VERSION 5.8 ;
UNITS
  DATABASE MICRONS 1000 ;
END UNITS
SITE core
  CLASS CORE ;
  SIZE 0.5 BY 2.0 ;
END core
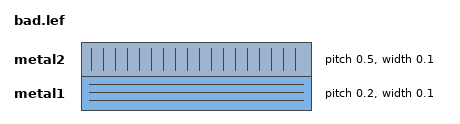
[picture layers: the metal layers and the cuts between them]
LAYER metal1
  TYPE ROUTING ;
  DIRECTION HORIZONTAL ;
  PITCH 0.2 ;
  WIDTH 0.1 ;
END metal1
LAYER metal2
  TYPE ROUTING ;
  DIRECTION VERTICAL ;
  PITCH 0.5 ;
  OFFSET 0.25 ;
  WIDTH 0.1 ;
END metal2
# clean: 0.5 x 2.0 = area 1, pins on track crossings
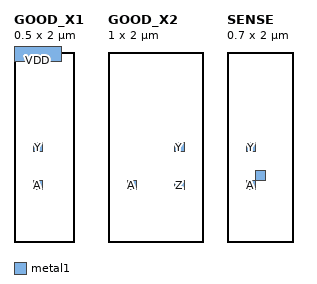
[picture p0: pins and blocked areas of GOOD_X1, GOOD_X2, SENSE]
MACRO GOOD_X1
  CLASS CORE ;
  SIZE 0.5 BY 2.0 ;
  SITE core ;
  PIN A
    DIRECTION INPUT ;
    PORT
      LAYER metal1 ;
        RECT 0.20 0.55 0.30 0.65 ;
    END
  END A
  PIN Y
    DIRECTION OUTPUT ;
    PORT
      LAYER metal1 ;
        RECT 0.20 0.95 0.30 1.05 ;
    END
  END Y
  PIN VDD
    DIRECTION INOUT ;
    USE POWER ;
    PORT
      LAYER metal1 ;
        RECT 0 1.9 0.5 2.1 ;
    END
  END VDD
END GOOD_X1
# LEF002: 1 x 2 = 2, the Liberty area is 0.9. LEF003: A is an output here, and there is a pin Z
MACRO GOOD_X2
  CLASS CORE ;
  SIZE 1.0 BY 2.0 ;
  SITE core ;
  PIN A
    DIRECTION OUTPUT ;
    PORT
      LAYER metal1 ;
        RECT 0.20 0.55 0.30 0.65 ;
    END
  END A
  PIN Y
    DIRECTION OUTPUT ;
    PORT
      LAYER metal1 ;
        RECT 0.70 0.95 0.80 1.05 ;
    END
  END Y
  PIN Z
    DIRECTION INPUT ;
    PORT
      LAYER metal1 ;
        RECT 0.70 0.55 0.80 0.65 ;
    END
  END Z
END GOOD_X2
# LEF004: 0.7 is not a multiple of 0.5. LEF005: B's shape misses every track. LEF003: no C
MACRO SENSE
  CLASS CORE ;
  SIZE 0.7 BY 2.0 ;
  SITE core ;
  PIN A
    DIRECTION INPUT ;
    PORT
      LAYER metal1 ;
        RECT 0.20 0.55 0.30 0.65 ;
    END
  END A
  PIN B
    DIRECTION INPUT ;
    PORT
      LAYER metal1 ;
        RECT 0.30 0.65 0.40 0.75 ;
    END
  END B
  PIN Y
    DIRECTION OUTPUT ;
    PORT
      LAYER metal1 ;
        RECT 0.20 0.95 0.30 1.05 ;
    END
  END Y
END SENSE
END LIBRARY
